VERSION 5.7 ;
  NOWIREEXTENSIONATPIN ON ;
  DIVIDERCHAR "/" ;
  BUSBITCHARS "[]" ;
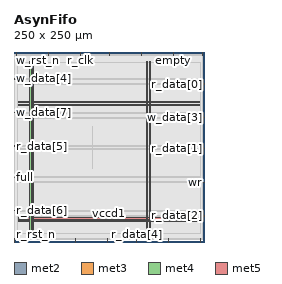
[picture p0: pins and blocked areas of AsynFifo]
MACRO AsynFifo
  CLASS BLOCK ;
  FOREIGN AsynFifo ;
  ORIGIN 0.000 0.000 ;
  SIZE 250.000 BY 250.000 ;
  PIN empty
    DIRECTION OUTPUT TRISTATE ;
    USE SIGNAL ;
    ANTENNADIFFAREA 0.795200 ;
    PORT
      LAYER met2 ;
        RECT 209.390 246.000 209.670 250.000 ;
    END
  END empty
  PIN full
    DIRECTION OUTPUT TRISTATE ;
    USE SIGNAL ;
    ANTENNADIFFAREA 0.795200 ;
    PORT
      LAYER met3 ;
        RECT 0.000 85.040 4.000 85.640 ;
    END
  END full
  PIN r_clk
    DIRECTION INPUT ;
    USE SIGNAL ;
    ANTENNAGATEAREA 0.126000 ;
    PORT
      LAYER met2 ;
        RECT 87.030 246.000 87.310 250.000 ;
    END
  END r_clk
  PIN r_data[0]
    DIRECTION OUTPUT TRISTATE ;
    USE SIGNAL ;
    ANTENNADIFFAREA 0.445500 ;
    PORT
      LAYER met3 ;
        RECT 246.000 207.440 250.000 208.040 ;
    END
  END r_data[0]
  PIN r_data[1]
    DIRECTION OUTPUT TRISTATE ;
    USE SIGNAL ;
    ANTENNADIFFAREA 0.445500 ;
    PORT
      LAYER met3 ;
        RECT 246.000 122.440 250.000 123.040 ;
    END
  END r_data[1]
  PIN r_data[2]
    DIRECTION OUTPUT TRISTATE ;
    USE SIGNAL ;
    ANTENNADIFFAREA 0.795200 ;
    PORT
      LAYER met3 ;
        RECT 246.000 34.040 250.000 34.640 ;
    END
  END r_data[2]
  PIN r_data[3]
    DIRECTION OUTPUT TRISTATE ;
    USE SIGNAL ;
    ANTENNADIFFAREA 0.795200 ;
    PORT
      LAYER met2 ;
        RECT 248.030 246.000 248.310 250.000 ;
    END
  END r_data[3]
  PIN r_data[4]
    DIRECTION OUTPUT TRISTATE ;
    USE SIGNAL ;
    ANTENNADIFFAREA 0.795200 ;
    PORT
      LAYER met2 ;
        RECT 161.090 0.000 161.370 4.000 ;
    END
  END r_data[4]
  PIN r_data[5]
    DIRECTION OUTPUT TRISTATE ;
    USE SIGNAL ;
    ANTENNADIFFAREA 0.795200 ;
    PORT
      LAYER met3 ;
        RECT 0.000 125.840 4.000 126.440 ;
    END
  END r_data[5]
  PIN r_data[6]
    DIRECTION OUTPUT TRISTATE ;
    USE SIGNAL ;
    ANTENNADIFFAREA 0.795200 ;
    PORT
      LAYER met3 ;
        RECT 0.000 40.840 4.000 41.440 ;
    END
  END r_data[6]
  PIN r_data[7]
    DIRECTION OUTPUT TRISTATE ;
    USE SIGNAL ;
    ANTENNADIFFAREA 0.795200 ;
    PORT
      LAYER met2 ;
        RECT 202.950 0.000 203.230 4.000 ;
    END
  END r_data[7]
  PIN r_rst_n
    DIRECTION INPUT ;
    USE SIGNAL ;
    ANTENNAGATEAREA 0.213000 ;
    PORT
      LAYER met2 ;
        RECT 0.090 0.000 0.370 4.000 ;
    END
  END r_rst_n
  PIN rd
    DIRECTION INPUT ;
    USE SIGNAL ;
    ANTENNAGATEAREA 0.159000 ;
    PORT
      LAYER met2 ;
        RECT 38.730 0.000 39.010 4.000 ;
    END
  END rd
  PIN vccd1
    DIRECTION INOUT ;
    USE POWER ;
    PORT
      LAYER met4 ;
        RECT 21.040 10.640 22.640 236.880 ;
    END
    PORT
      LAYER met4 ;
        RECT 174.640 10.640 176.240 236.880 ;
    END
    PORT
      LAYER met5 ;
        RECT 5.280 26.730 244.500 28.330 ;
    END
    PORT
      LAYER met5 ;
        RECT 5.280 179.910 244.500 181.510 ;
    END
  END vccd1
  PIN vssd1
    DIRECTION INOUT ;
    USE GROUND ;
    PORT
      LAYER met4 ;
        RECT 24.340 10.640 25.940 236.880 ;
    END
    PORT
      LAYER met4 ;
        RECT 177.940 10.640 179.540 236.880 ;
    END
    PORT
      LAYER met5 ;
        RECT 5.280 30.030 244.500 31.630 ;
    END
    PORT
      LAYER met5 ;
        RECT 5.280 183.210 244.500 184.810 ;
    END
  END vssd1
  PIN w_clk
    DIRECTION INPUT ;
    USE SIGNAL ;
    ANTENNAGATEAREA 0.852000 ;
    PORT
      LAYER met2 ;
        RECT 125.670 246.000 125.950 250.000 ;
    END
  END w_clk
  PIN w_data[0]
    DIRECTION INPUT ;
    USE SIGNAL ;
    ANTENNAGATEAREA 0.426000 ;
    PORT
      LAYER met2 ;
        RECT 244.810 0.000 245.090 4.000 ;
    END
  END w_data[0]
  PIN w_data[1]
    DIRECTION INPUT ;
    USE SIGNAL ;
    ANTENNAGATEAREA 0.247500 ;
    PORT
      LAYER met2 ;
        RECT 80.590 0.000 80.870 4.000 ;
    END
  END w_data[1]
  PIN w_data[2]
    DIRECTION INPUT ;
    USE SIGNAL ;
    ANTENNAGATEAREA 0.247500 ;
    PORT
      LAYER met2 ;
        RECT 45.170 246.000 45.450 250.000 ;
    END
  END w_data[2]
  PIN w_data[3]
    DIRECTION INPUT ;
    USE SIGNAL ;
    ANTENNAGATEAREA 0.247500 ;
    PORT
      LAYER met3 ;
        RECT 246.000 163.240 250.000 163.840 ;
    END
  END w_data[3]
  PIN w_data[4]
    DIRECTION INPUT ;
    USE SIGNAL ;
    ANTENNAGATEAREA 0.247500 ;
    PORT
      LAYER met3 ;
        RECT 0.000 214.240 4.000 214.840 ;
    END
  END w_data[4]
  PIN w_data[5]
    DIRECTION INPUT ;
    USE SIGNAL ;
    ANTENNAGATEAREA 0.247500 ;
    PORT
      LAYER met2 ;
        RECT 167.530 246.000 167.810 250.000 ;
    END
  END w_data[5]
  PIN w_data[6]
    DIRECTION INPUT ;
    USE SIGNAL ;
    ANTENNAGATEAREA 0.247500 ;
    PORT
      LAYER met2 ;
        RECT 122.450 0.000 122.730 4.000 ;
    END
  END w_data[6]
  PIN w_data[7]
    DIRECTION INPUT ;
    USE SIGNAL ;
    ANTENNAGATEAREA 0.247500 ;
    PORT
      LAYER met3 ;
        RECT 0.000 170.040 4.000 170.640 ;
    END
  END w_data[7]
  PIN w_rst_n
    DIRECTION INPUT ;
    USE SIGNAL ;
    ANTENNAGATEAREA 0.213000 ;
    PORT
      LAYER met2 ;
        RECT 3.310 246.000 3.590 250.000 ;
    END
  END w_rst_n
  PIN wr
    DIRECTION INPUT ;
    USE SIGNAL ;
    ANTENNAGATEAREA 0.213000 ;
    PORT
      LAYER met3 ;
        RECT 246.000 78.240 250.000 78.840 ;
    END
  END wr
  OBS
      LAYER li1 ;
        RECT 5.520 10.795 244.260 236.725 ;
      LAYER met1 ;
        RECT 0.070 10.640 248.330 236.880 ;
      LAYER met2 ;
        RECT 0.100 245.720 3.030 246.570 ;
        RECT 3.870 245.720 44.890 246.570 ;
        RECT 45.730 245.720 86.750 246.570 ;
        RECT 87.590 245.720 125.390 246.570 ;
        RECT 126.230 245.720 167.250 246.570 ;
        RECT 168.090 245.720 209.110 246.570 ;
        RECT 209.950 245.720 247.750 246.570 ;
        RECT 0.100 4.280 248.300 245.720 ;
        RECT 0.650 3.670 38.450 4.280 ;
        RECT 39.290 3.670 80.310 4.280 ;
        RECT 81.150 3.670 122.170 4.280 ;
        RECT 123.010 3.670 160.810 4.280 ;
        RECT 161.650 3.670 202.670 4.280 ;
        RECT 203.510 3.670 244.530 4.280 ;
        RECT 245.370 3.670 248.300 4.280 ;
      LAYER met3 ;
        RECT 3.990 215.240 246.000 236.805 ;
        RECT 4.400 213.840 246.000 215.240 ;
        RECT 3.990 208.440 246.000 213.840 ;
        RECT 3.990 207.040 245.600 208.440 ;
        RECT 3.990 171.040 246.000 207.040 ;
        RECT 4.400 169.640 246.000 171.040 ;
        RECT 3.990 164.240 246.000 169.640 ;
        RECT 3.990 162.840 245.600 164.240 ;
        RECT 3.990 126.840 246.000 162.840 ;
        RECT 4.400 125.440 246.000 126.840 ;
        RECT 3.990 123.440 246.000 125.440 ;
        RECT 3.990 122.040 245.600 123.440 ;
        RECT 3.990 86.040 246.000 122.040 ;
        RECT 4.400 84.640 246.000 86.040 ;
        RECT 3.990 79.240 246.000 84.640 ;
        RECT 3.990 77.840 245.600 79.240 ;
        RECT 3.990 41.840 246.000 77.840 ;
        RECT 4.400 40.440 246.000 41.840 ;
        RECT 3.990 35.040 246.000 40.440 ;
        RECT 3.990 33.640 245.600 35.040 ;
        RECT 3.990 10.715 246.000 33.640 ;
      LAYER met4 ;
        RECT 103.335 96.735 103.665 151.465 ;
  END
END AsynFifo
END LIBRARY

